VERSION 5.7 ;
  NOWIREEXTENSIONATPIN ON ;
  DIVIDERCHAR "/" ;
  BUSBITCHARS "[]" ;
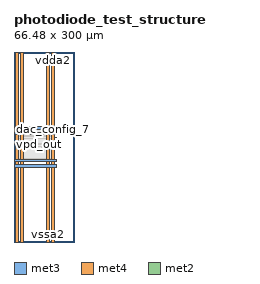
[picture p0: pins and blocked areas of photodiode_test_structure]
MACRO photodiode_test_structure
  CLASS BLOCK ;
  FOREIGN photodiode_test_structure ;
  ORIGIN 0.000 115.415 ;
  SIZE 66.480 BY 300.000 ;
  PIN vdda2
    ANTENNADIFFAREA 31.261799 ;
    PORT
      LAYER met3 ;
        RECT 0.000 62.170 66.480 66.170 ;
    END
    PORT
      LAYER met3 ;
        RECT 0.000 3.000 66.480 7.000 ;
    END
    PORT
      LAYER met4 ;
        RECT 59.480 -115.415 63.480 184.585 ;
    END
    PORT
      LAYER met4 ;
        RECT 3.000 -115.415 7.000 184.585 ;
    END
  END vdda2
  PIN vssa2
    ANTENNAGATEAREA 1.600000 ;
    ANTENNADIFFAREA 55.168049 ;
    PORT
      LAYER met3 ;
        RECT 0.000 54.170 66.480 58.170 ;
    END
    PORT
      LAYER met3 ;
        RECT 0.000 11.000 66.480 15.000 ;
    END
    PORT
      LAYER met4 ;
        RECT 51.480 -115.415 55.480 184.585 ;
    END
    PORT
      LAYER met4 ;
        RECT 11.000 -115.415 15.000 184.585 ;
    END
  END vssa2
  PIN vpd_out
    ANTENNAGATEAREA 38.399998 ;
    ANTENNADIFFAREA 13.040000 ;
    PORT
      LAYER met2 ;
        RECT 0.000 38.440 3.000 39.080 ;
    END
  END vpd_out
  PIN dac_config_7
    ANTENNAGATEAREA 8.000000 ;
    PORT
      LAYER met2 ;
        RECT 63.480 49.025 66.480 50.325 ;
    END
  END dac_config_7
  PIN dac_config_8
    ANTENNAGATEAREA 0.150000 ;
    PORT
      LAYER met2 ;
        RECT 63.480 34.875 66.480 35.875 ;
    END
  END dac_config_8
  OBS
      LAYER nwell ;
        RECT 14.995 14.995 51.485 54.175 ;
      LAYER li1 ;
        RECT 15.125 15.125 51.355 54.045 ;
      LAYER met1 ;
        RECT 15.065 15.065 51.415 54.105 ;
      LAYER met2 ;
        RECT 3.000 54.450 63.480 66.170 ;
        RECT 3.000 53.470 25.240 54.450 ;
        RECT 33.840 53.470 63.480 54.450 ;
        RECT 3.000 50.605 63.480 53.470 ;
        RECT 3.000 48.745 63.200 50.605 ;
        RECT 3.000 39.360 63.480 48.745 ;
        RECT 3.280 38.160 63.480 39.360 ;
        RECT 3.000 36.155 63.480 38.160 ;
        RECT 3.000 34.595 63.200 36.155 ;
        RECT 3.000 16.215 63.480 34.595 ;
        RECT 3.000 15.075 21.500 16.215 ;
        RECT 46.685 15.075 63.480 16.215 ;
        RECT 3.000 11.000 63.480 15.075 ;
      LAYER met3 ;
        RECT 42.850 27.345 48.550 33.050 ;
      LAYER met4 ;
        RECT 42.850 27.345 48.550 33.050 ;
      LAYER met5 ;
        RECT 42.850 27.345 48.550 33.050 ;
  END
END photodiode_test_structure
END LIBRARY

